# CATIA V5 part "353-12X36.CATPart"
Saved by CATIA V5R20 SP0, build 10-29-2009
Part number: 353-12X36
Definition: NONE
Nomenclature: 353-12X36
Source: Unknown
Description: 353-12X36
Bounding box of the stored display mesh (mm): x -5 to 31, y -11 to 11, z -11 to 11
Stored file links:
  C:\Users\Utente\Desktop\IO LAVORO\3D X SITO CF\X SITO\PLASTICA\353\353-12X36.CATPart

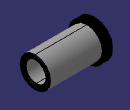
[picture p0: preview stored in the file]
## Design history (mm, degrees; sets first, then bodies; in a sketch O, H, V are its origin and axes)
Body1 "353-12X36" (main body)
  Solid1: solid without history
